VERSION 5.7 ;
BUSBITCHARS "[]" ;
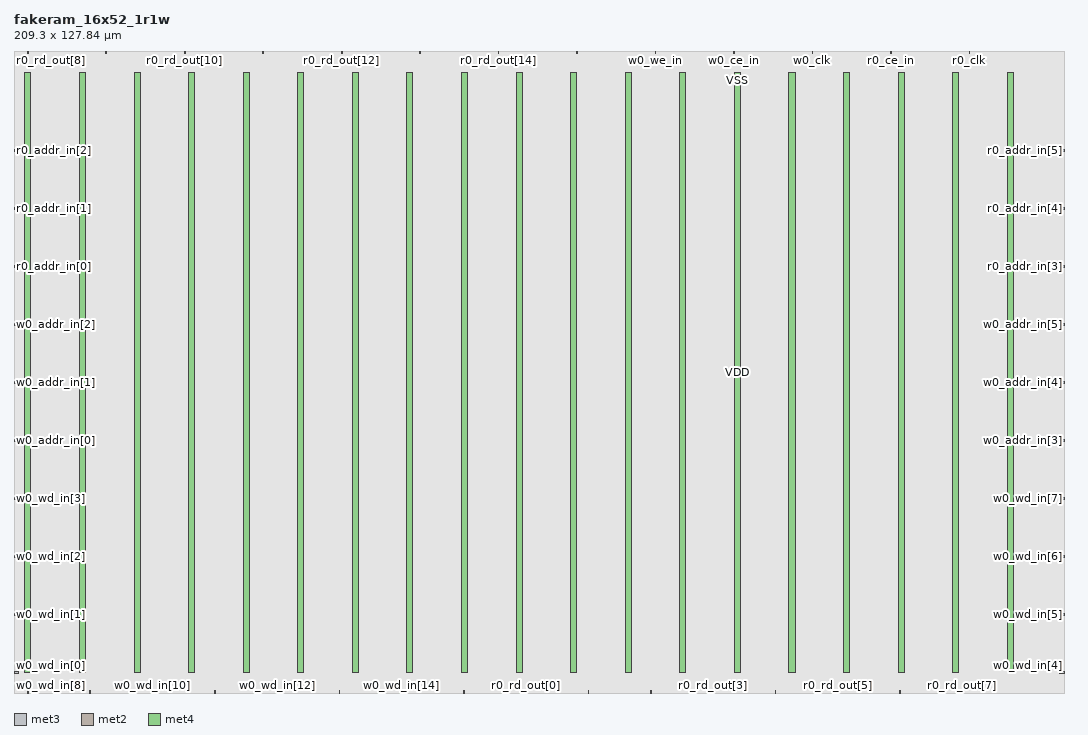
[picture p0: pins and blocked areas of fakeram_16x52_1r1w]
MACRO fakeram_16x52_1r1w
  FOREIGN fakeram_16x52_1r1w 0 0 ;
  SYMMETRY X Y R90 ;
  SIZE 209.300 BY 127.840 ;
  CLASS BLOCK ;
  PIN w0_wd_in[0]
    DIRECTION INPUT ;
    USE SIGNAL ;
    SHAPE ABUTMENT ;
    PORT
      LAYER met3 ;
      RECT 0.000 3.930 0.900 4.230 ;
    END
  END w0_wd_in[0]
  PIN w0_wd_in[1]
    DIRECTION INPUT ;
    USE SIGNAL ;
    SHAPE ABUTMENT ;
    PORT
      LAYER met3 ;
      RECT 0.000 15.490 0.900 15.790 ;
    END
  END w0_wd_in[1]
  PIN w0_wd_in[2]
    DIRECTION INPUT ;
    USE SIGNAL ;
    SHAPE ABUTMENT ;
    PORT
      LAYER met3 ;
      RECT 0.000 27.050 0.900 27.350 ;
    END
  END w0_wd_in[2]
  PIN w0_wd_in[3]
    DIRECTION INPUT ;
    USE SIGNAL ;
    SHAPE ABUTMENT ;
    PORT
      LAYER met3 ;
      RECT 0.000 38.610 0.900 38.910 ;
    END
  END w0_wd_in[3]
  PIN w0_wd_in[4]
    DIRECTION INPUT ;
    USE SIGNAL ;
    SHAPE ABUTMENT ;
    PORT
      LAYER met3 ;
      RECT 208.400 3.930 209.300 4.230 ;
    END
  END w0_wd_in[4]
  PIN w0_wd_in[5]
    DIRECTION INPUT ;
    USE SIGNAL ;
    SHAPE ABUTMENT ;
    PORT
      LAYER met3 ;
      RECT 208.400 15.490 209.300 15.790 ;
    END
  END w0_wd_in[5]
  PIN w0_wd_in[6]
    DIRECTION INPUT ;
    USE SIGNAL ;
    SHAPE ABUTMENT ;
    PORT
      LAYER met3 ;
      RECT 208.400 27.050 209.300 27.350 ;
    END
  END w0_wd_in[6]
  PIN w0_wd_in[7]
    DIRECTION INPUT ;
    USE SIGNAL ;
    SHAPE ABUTMENT ;
    PORT
      LAYER met3 ;
      RECT 208.400 38.610 209.300 38.910 ;
    END
  END w0_wd_in[7]
  PIN w0_wd_in[8]
    DIRECTION OUTPUT ;
    USE SIGNAL ;
    SHAPE ABUTMENT ;
    PORT
      LAYER met2 ;
      RECT 2.690 0.000 2.830 0.420 ;
    END
  END w0_wd_in[8]
  PIN w0_wd_in[9]
    DIRECTION OUTPUT ;
    USE SIGNAL ;
    SHAPE ABUTMENT ;
    PORT
      LAYER met2 ;
      RECT 15.110 0.000 15.250 0.420 ;
    END
  END w0_wd_in[9]
  PIN w0_wd_in[10]
    DIRECTION OUTPUT ;
    USE SIGNAL ;
    SHAPE ABUTMENT ;
    PORT
      LAYER met2 ;
      RECT 27.530 0.000 27.670 0.420 ;
    END
  END w0_wd_in[10]
  PIN w0_wd_in[11]
    DIRECTION OUTPUT ;
    USE SIGNAL ;
    SHAPE ABUTMENT ;
    PORT
      LAYER met2 ;
      RECT 39.950 0.000 40.090 0.420 ;
    END
  END w0_wd_in[11]
  PIN w0_wd_in[12]
    DIRECTION OUTPUT ;
    USE SIGNAL ;
    SHAPE ABUTMENT ;
    PORT
      LAYER met2 ;
      RECT 52.370 0.000 52.510 0.420 ;
    END
  END w0_wd_in[12]
  PIN w0_wd_in[13]
    DIRECTION OUTPUT ;
    USE SIGNAL ;
    SHAPE ABUTMENT ;
    PORT
      LAYER met2 ;
      RECT 64.790 0.000 64.930 0.420 ;
    END
  END w0_wd_in[13]
  PIN w0_wd_in[14]
    DIRECTION OUTPUT ;
    USE SIGNAL ;
    SHAPE ABUTMENT ;
    PORT
      LAYER met2 ;
      RECT 77.210 0.000 77.350 0.420 ;
    END
  END w0_wd_in[14]
  PIN w0_wd_in[15]
    DIRECTION OUTPUT ;
    USE SIGNAL ;
    SHAPE ABUTMENT ;
    PORT
      LAYER met2 ;
      RECT 89.630 0.000 89.770 0.420 ;
    END
  END w0_wd_in[15]
  PIN r0_rd_out[0]
    DIRECTION OUTPUT ;
    USE SIGNAL ;
    SHAPE ABUTMENT ;
    PORT
      LAYER met2 ;
      RECT 102.050 0.000 102.190 0.420 ;
    END
  END r0_rd_out[0]
  PIN r0_rd_out[1]
    DIRECTION OUTPUT ;
    USE SIGNAL ;
    SHAPE ABUTMENT ;
    PORT
      LAYER met2 ;
      RECT 114.470 0.000 114.610 0.420 ;
    END
  END r0_rd_out[1]
  PIN r0_rd_out[2]
    DIRECTION OUTPUT ;
    USE SIGNAL ;
    SHAPE ABUTMENT ;
    PORT
      LAYER met2 ;
      RECT 126.890 0.000 127.030 0.420 ;
    END
  END r0_rd_out[2]
  PIN r0_rd_out[3]
    DIRECTION OUTPUT ;
    USE SIGNAL ;
    SHAPE ABUTMENT ;
    PORT
      LAYER met2 ;
      RECT 139.310 0.000 139.450 0.420 ;
    END
  END r0_rd_out[3]
  PIN r0_rd_out[4]
    DIRECTION OUTPUT ;
    USE SIGNAL ;
    SHAPE ABUTMENT ;
    PORT
      LAYER met2 ;
      RECT 151.730 0.000 151.870 0.420 ;
    END
  END r0_rd_out[4]
  PIN r0_rd_out[5]
    DIRECTION OUTPUT ;
    USE SIGNAL ;
    SHAPE ABUTMENT ;
    PORT
      LAYER met2 ;
      RECT 164.150 0.000 164.290 0.420 ;
    END
  END r0_rd_out[5]
  PIN r0_rd_out[6]
    DIRECTION OUTPUT ;
    USE SIGNAL ;
    SHAPE ABUTMENT ;
    PORT
      LAYER met2 ;
      RECT 176.570 0.000 176.710 0.420 ;
    END
  END r0_rd_out[6]
  PIN r0_rd_out[7]
    DIRECTION OUTPUT ;
    USE SIGNAL ;
    SHAPE ABUTMENT ;
    PORT
      LAYER met2 ;
      RECT 188.990 0.000 189.130 0.420 ;
    END
  END r0_rd_out[7]
  PIN r0_rd_out[8]
    DIRECTION OUTPUT ;
    USE SIGNAL ;
    SHAPE ABUTMENT ;
    PORT
      LAYER met2 ;
      RECT 2.690 127.420 2.830 127.840 ;
    END
  END r0_rd_out[8]
  PIN r0_rd_out[9]
    DIRECTION OUTPUT ;
    USE SIGNAL ;
    SHAPE ABUTMENT ;
    PORT
      LAYER met2 ;
      RECT 18.330 127.420 18.470 127.840 ;
    END
  END r0_rd_out[9]
  PIN r0_rd_out[10]
    DIRECTION OUTPUT ;
    USE SIGNAL ;
    SHAPE ABUTMENT ;
    PORT
      LAYER met2 ;
      RECT 33.970 127.420 34.110 127.840 ;
    END
  END r0_rd_out[10]
  PIN r0_rd_out[11]
    DIRECTION OUTPUT ;
    USE SIGNAL ;
    SHAPE ABUTMENT ;
    PORT
      LAYER met2 ;
      RECT 49.610 127.420 49.750 127.840 ;
    END
  END r0_rd_out[11]
  PIN r0_rd_out[12]
    DIRECTION OUTPUT ;
    USE SIGNAL ;
    SHAPE ABUTMENT ;
    PORT
      LAYER met2 ;
      RECT 65.250 127.420 65.390 127.840 ;
    END
  END r0_rd_out[12]
  PIN r0_rd_out[13]
    DIRECTION OUTPUT ;
    USE SIGNAL ;
    SHAPE ABUTMENT ;
    PORT
      LAYER met2 ;
      RECT 80.890 127.420 81.030 127.840 ;
    END
  END r0_rd_out[13]
  PIN r0_rd_out[14]
    DIRECTION OUTPUT ;
    USE SIGNAL ;
    SHAPE ABUTMENT ;
    PORT
      LAYER met2 ;
      RECT 96.530 127.420 96.670 127.840 ;
    END
  END r0_rd_out[14]
  PIN r0_rd_out[15]
    DIRECTION OUTPUT ;
    USE SIGNAL ;
    SHAPE ABUTMENT ;
    PORT
      LAYER met2 ;
      RECT 112.170 127.420 112.310 127.840 ;
    END
  END r0_rd_out[15]
  PIN w0_addr_in[0]
    DIRECTION INPUT ;
    USE SIGNAL ;
    SHAPE ABUTMENT ;
    PORT
      LAYER met3 ;
      RECT 0.000 50.170 0.900 50.470 ;
    END
  END w0_addr_in[0]
  PIN w0_addr_in[1]
    DIRECTION INPUT ;
    USE SIGNAL ;
    SHAPE ABUTMENT ;
    PORT
      LAYER met3 ;
      RECT 0.000 61.730 0.900 62.030 ;
    END
  END w0_addr_in[1]
  PIN w0_addr_in[2]
    DIRECTION INPUT ;
    USE SIGNAL ;
    SHAPE ABUTMENT ;
    PORT
      LAYER met3 ;
      RECT 0.000 73.290 0.900 73.590 ;
    END
  END w0_addr_in[2]
  PIN w0_addr_in[3]
    DIRECTION INPUT ;
    USE SIGNAL ;
    SHAPE ABUTMENT ;
    PORT
      LAYER met3 ;
      RECT 208.400 50.170 209.300 50.470 ;
    END
  END w0_addr_in[3]
  PIN w0_addr_in[4]
    DIRECTION INPUT ;
    USE SIGNAL ;
    SHAPE ABUTMENT ;
    PORT
      LAYER met3 ;
      RECT 208.400 61.730 209.300 62.030 ;
    END
  END w0_addr_in[4]
  PIN w0_addr_in[5]
    DIRECTION INPUT ;
    USE SIGNAL ;
    SHAPE ABUTMENT ;
    PORT
      LAYER met3 ;
      RECT 208.400 73.290 209.300 73.590 ;
    END
  END w0_addr_in[5]
  PIN r0_addr_in[0]
    DIRECTION INPUT ;
    USE SIGNAL ;
    SHAPE ABUTMENT ;
    PORT
      LAYER met3 ;
      RECT 0.000 84.850 0.900 85.150 ;
    END
  END r0_addr_in[0]
  PIN r0_addr_in[1]
    DIRECTION INPUT ;
    USE SIGNAL ;
    SHAPE ABUTMENT ;
    PORT
      LAYER met3 ;
      RECT 0.000 96.410 0.900 96.710 ;
    END
  END r0_addr_in[1]
  PIN r0_addr_in[2]
    DIRECTION INPUT ;
    USE SIGNAL ;
    SHAPE ABUTMENT ;
    PORT
      LAYER met3 ;
      RECT 0.000 107.970 0.900 108.270 ;
    END
  END r0_addr_in[2]
  PIN r0_addr_in[3]
    DIRECTION INPUT ;
    USE SIGNAL ;
    SHAPE ABUTMENT ;
    PORT
      LAYER met3 ;
      RECT 208.400 84.850 209.300 85.150 ;
    END
  END r0_addr_in[3]
  PIN r0_addr_in[4]
    DIRECTION INPUT ;
    USE SIGNAL ;
    SHAPE ABUTMENT ;
    PORT
      LAYER met3 ;
      RECT 208.400 96.410 209.300 96.710 ;
    END
  END r0_addr_in[4]
  PIN r0_addr_in[5]
    DIRECTION INPUT ;
    USE SIGNAL ;
    SHAPE ABUTMENT ;
    PORT
      LAYER met3 ;
      RECT 208.400 107.970 209.300 108.270 ;
    END
  END r0_addr_in[5]
  PIN w0_we_in
    DIRECTION INPUT ;
    USE SIGNAL ;
    SHAPE ABUTMENT ;
    PORT
      LAYER met2 ;
      RECT 127.810 127.420 127.950 127.840 ;
    END
  END w0_we_in
  PIN w0_ce_in
    DIRECTION INPUT ;
    USE SIGNAL ;
    SHAPE ABUTMENT ;
    PORT
      LAYER met2 ;
      RECT 143.450 127.420 143.590 127.840 ;
    END
  END w0_ce_in
  PIN w0_clk
    DIRECTION INPUT ;
    USE SIGNAL ;
    SHAPE ABUTMENT ;
    PORT
      LAYER met2 ;
      RECT 159.090 127.420 159.230 127.840 ;
    END
  END w0_clk
  PIN r0_ce_in
    DIRECTION INPUT ;
    USE SIGNAL ;
    SHAPE ABUTMENT ;
    PORT
      LAYER met2 ;
      RECT 174.730 127.420 174.870 127.840 ;
    END
  END r0_ce_in
  PIN r0_clk
    DIRECTION INPUT ;
    USE SIGNAL ;
    SHAPE ABUTMENT ;
    PORT
      LAYER met2 ;
      RECT 190.370 127.420 190.510 127.840 ;
    END
  END r0_clk
  PIN VSS
    DIRECTION INOUT ;
    USE GROUND ;
    PORT
      LAYER met4 ;
      RECT 2.160 4.080 3.360 123.760 ;
      RECT 13.040 4.080 14.240 123.760 ;
      RECT 23.920 4.080 25.120 123.760 ;
      RECT 34.800 4.080 36.000 123.760 ;
      RECT 45.680 4.080 46.880 123.760 ;
      RECT 56.560 4.080 57.760 123.760 ;
      RECT 67.440 4.080 68.640 123.760 ;
      RECT 78.320 4.080 79.520 123.760 ;
      RECT 89.200 4.080 90.400 123.760 ;
      RECT 100.080 4.080 101.280 123.760 ;
      RECT 110.960 4.080 112.160 123.760 ;
      RECT 121.840 4.080 123.040 123.760 ;
      RECT 132.720 4.080 133.920 123.760 ;
      RECT 143.600 4.080 144.800 123.760 ;
      RECT 154.480 4.080 155.680 123.760 ;
      RECT 165.360 4.080 166.560 123.760 ;
      RECT 176.240 4.080 177.440 123.760 ;
      RECT 187.120 4.080 188.320 123.760 ;
      RECT 198.000 4.080 199.200 123.760 ;
    END
  END VSS
  PIN VDD
    DIRECTION INOUT ;
    USE POWER ;
    PORT
      LAYER met4 ;
      RECT 2.160 4.080 3.360 123.760 ;
      RECT 13.040 4.080 14.240 123.760 ;
      RECT 23.920 4.080 25.120 123.760 ;
      RECT 34.800 4.080 36.000 123.760 ;
      RECT 45.680 4.080 46.880 123.760 ;
      RECT 56.560 4.080 57.760 123.760 ;
      RECT 67.440 4.080 68.640 123.760 ;
      RECT 78.320 4.080 79.520 123.760 ;
      RECT 89.200 4.080 90.400 123.760 ;
      RECT 100.080 4.080 101.280 123.760 ;
      RECT 110.960 4.080 112.160 123.760 ;
      RECT 121.840 4.080 123.040 123.760 ;
      RECT 132.720 4.080 133.920 123.760 ;
      RECT 143.600 4.080 144.800 123.760 ;
      RECT 154.480 4.080 155.680 123.760 ;
      RECT 165.360 4.080 166.560 123.760 ;
      RECT 176.240 4.080 177.440 123.760 ;
      RECT 187.120 4.080 188.320 123.760 ;
      RECT 198.000 4.080 199.200 123.760 ;
    END
  END VDD
  OBS
    LAYER met1 ;
    RECT 0 0 209.300 127.840 ;
    LAYER met2 ;
    RECT 0 0 209.300 127.840 ;
    LAYER met3 ;
    RECT 0 0 209.300 127.840 ;
    LAYER met4 ;
    RECT 0 0 209.300 127.840 ;
  END
END fakeram_16x52_1r1w

END LIBRARY
